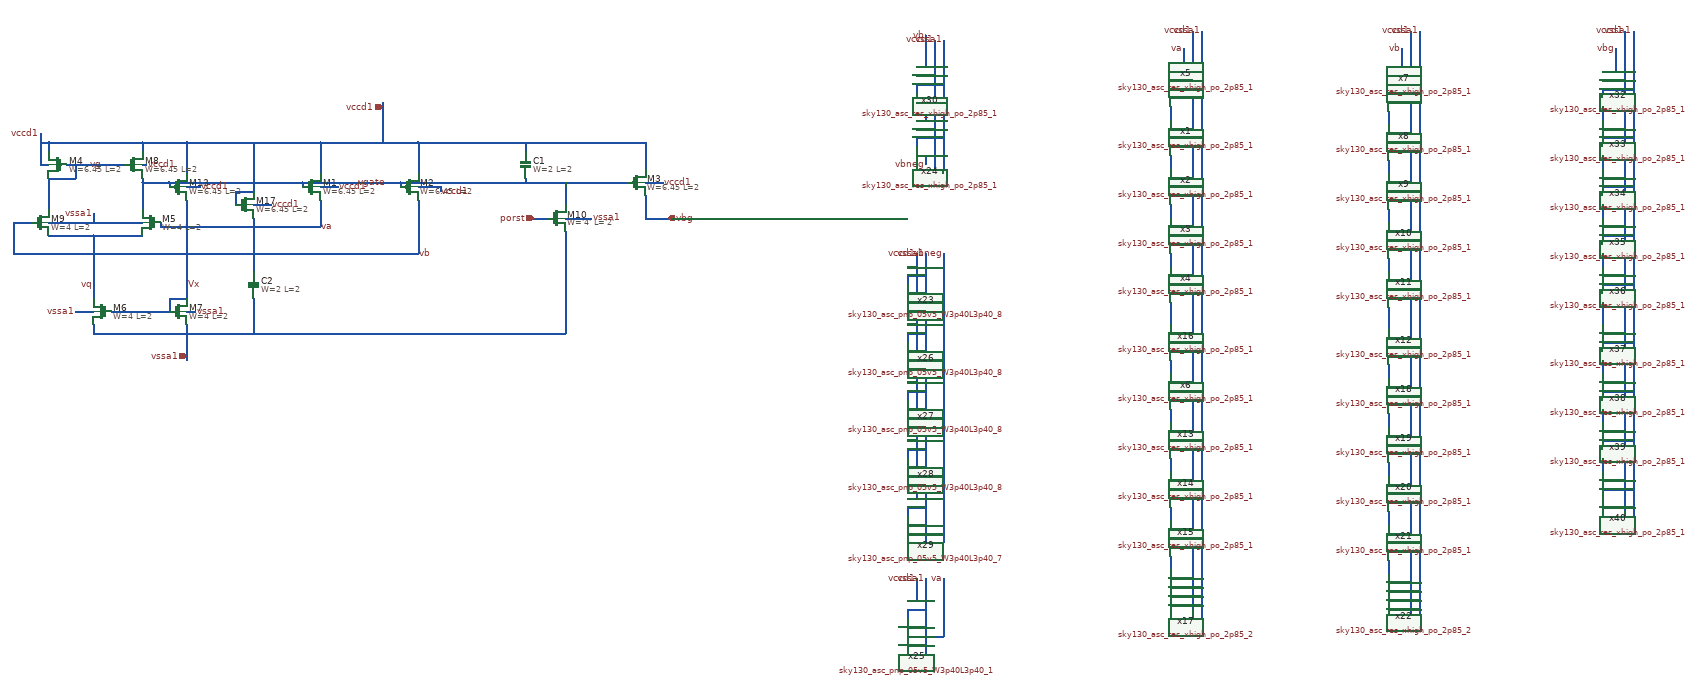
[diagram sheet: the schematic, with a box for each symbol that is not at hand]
v {xschem version=3.0.0 file_version=1.2 }
G {}
K {}
V {}
S {}
E {}
N 2040 520 2260 520 { lab=vccd1}
N 2260 520 2460 520 { lab=vccd1}
N 1430 600 1490 600 { lab=vg}
N 1490 570 1490 600 { lab=vg}
N 1470 570 1490 570 { lab=vg}
N 1490 570 1600 570 { lab=vg}
N 1430 520 1430 540 { lab=vccd1}
N 1430 600 1430 670 { lab=vg}
N 1640 610 1640 670 { lab=vgate}
N 1630 730 1640 730 { lab=vq}
N 1640 570 1650 570 { lab=vccd1}
N 1420 570 1430 570 { lab=vccd1}
N 1430 700 1440 700 { lab=vssa1}
N 1630 700 1640 700 { lab=vssa1}
N 1520 900 1530 900 { lab=vssa1}
N 1570 900 1700 900 { lab=Vx}
N 1740 900 1750 900 { lab=vssa1}
N 1700 870 1700 900 { lab=Vx}
N 1700 870 1740 870 { lab=Vx}
N 2650 520 2770 520 { lab=vccd1}
N 2260 520 2260 590 { lab=vccd1}
N 2770 610 2780 610 { lab=vccd1}
N 2220 610 2220 620 { lab=vgate}
N 2000 610 2000 620 { lab=vgate}
N 1740 620 1750 620 { lab=vccd1}
N 2040 620 2050 620 { lab=vccd1}
N 2040 520 2040 590 { lab=vccd1}
N 2260 620 2270 620 { lab=vccd1}
N 1780 520 2040 520 { lab=vccd1}
N 2700 610 2730 610 { lab=vgate}
N 1700 610 1700 620 { lab=vgate}
N 1740 520 1740 590 { lab=vccd1}
N 1910 710 2040 710 { lab=va}
N 2770 520 2770 580 { lab=vccd1}
N 1430 520 1640 520 { lab=vccd1}
N 1430 730 1440 730 { lab=vq}
N 1530 730 1630 730 { lab=vq}
N 2460 520 2650 520 { lab=vccd1}
N 1740 650 1740 840 { lab=Vx}
N 2000 610 2220 610 { lab=vgate}
N 2220 610 2700 610 { lab=vgate}
N 1440 730 1530 730 { lab=vq}
N 1640 600 1640 610 { lab=vgate}
N 1640 610 1700 610 { lab=vgate}
N 1640 520 1740 520 { lab=vccd1}
N 1440 700 1630 700 { lab=vssa1}
N 1740 520 1780 520 { lab=vccd1}
N 1840 610 2000 610 { lab=vgate}
N 1700 610 1840 610 { lab=vgate}
N 2590 690 2600 690 { lab=vssa1}
N 2590 610 2590 660 { lab=vgate}
N 2500 520 2500 540 { lab=vccd1}
N 2500 600 2500 610 { lab=vgate}
N 1830 710 1910 710 { lab=va}
N 1370 770 2150 770 { lab=#net1}
N 2040 650 2040 710 { lab=va}
N 1680 710 1830 710 { lab=va}
N 1680 700 1680 710 { lab=va}
N 1890 690 1890 710 { lab=va}
N 1850 630 1890 630 { lab=vccd1}
N 1850 630 1850 660 { lab=vccd1}
N 1890 520 1890 630 { lab=vccd1}
N 2770 690 2830 690 { lab=vbg}
N 2150 770 2260 770 { lab=#net1}
N 2180 450 2180 520 { lab=vccd1}
N 2780 610 2810 610 { lab=vccd1}
N 2310 620 2310 630 { lab=vccd1}
N 2270 620 2310 620 { lab=vccd1}
N 2050 620 2080 620 { lab=vccd1}
N 1750 620 1770 620 { lab=vccd1}
N 1640 520 1640 540 { lab=vccd1}
N 1410 570 1420 570 { lab=vccd1}
N 1410 500 1410 570 { lab=vccd1}
N 2600 690 2650 690 { lab=vssa1}
N 1890 660 1930 660 { lab=vccd1}
N 2510 690 2550 690 { lab=porst}
N 1750 900 1760 900 { lab=vssa1}
N 1490 900 1520 900 { lab=vssa1}
N 1530 680 1530 700 { lab=vssa1}
N 1350 700 1390 700 { lab=#net1}
N 1350 700 1350 770 { lab=#net1}
N 1350 770 1370 770 { lab=#net1}
N 2180 430 2180 450 { lab=vccd1}
N 4000 390 4000 1510 { lab=vccd1}
N 4000 310 4000 390 { lab=vccd1}
N 4020 310 4020 1590 { lab=vssa1}
N 4000 270 4000 310 { lab=vccd1}
N 4020 270 4020 310 { lab=vssa1}
N 4470 310 4470 370 { lab=vb}
N 4490 270 4490 310 { lab=vccd1}
N 4510 270 4510 310 { lab=vssa1}
N 4970 310 4970 390 { lab=vccd1}
N 4970 270 4970 310 { lab=vccd1}
N 4990 270 4990 310 { lab=vssa1}
N 4990 310 4990 1310 { lab=vssa1}
N 2770 640 2770 690 { lab=vbg}
N 3400 280 3400 350 { lab=vb}
N 3420 380 3420 500 { lab=vccd1}
N 3440 400 3440 520 { lab=vssa1}
N 3420 290 3420 380 { lab=vccd1}
N 3440 290 3440 400 { lab=vssa1}
N 2260 650 2260 740 { lab=#net1}
N 3380 770 3380 1280 { lab=vccd1}
N 3400 770 3400 1300 { lab=vssa1}
N 3440 770 3440 1340 { lab=vbneg}
N 1740 950 1740 1010 { lab=vssa1}
N 3440 1500 3440 1620 { lab=va}
N 1740 840 1740 870 { lab=Vx}
N 1530 930 1530 950 { lab=vssa1}
N 1530 950 1740 950 { lab=vssa1}
N 1740 930 1740 950 { lab=vssa1}
N 1530 730 1530 870 { lab=vq}
N 2590 720 2590 950 { lab=vssa1}
N 1740 950 2590 950 { lab=vssa1}
N 1890 710 1890 810 { lab=va}
N 1890 870 1890 950 { lab=vssa1}
N 2260 740 2260 770 { lab=#net1}
N 1410 520 1430 520 { lab=vccd1}
N 3380 350 3400 350 { lab=vb}
N 3380 370 3420 370 { lab=vccd1}
N 3380 390 3440 390 { lab=vssa1}
N 3380 430 3400 430 { lab=#net2}
N 3400 430 3400 470 { lab=#net2}
N 3380 470 3400 470 { lab=#net2}
N 3380 490 3420 490 { lab=vccd1}
N 3380 550 3400 550 { lab=vbneg}
N 3400 550 3400 570 { lab=vbneg}
N 3440 520 3440 530 { lab=vssa1}
N 3380 510 3440 510 { lab=vssa1}
N 3420 500 3420 580 { lab=vccd1}
N 3440 530 3440 590 { lab=vssa1}
N 3950 360 3980 360 { lab=va}
N 3980 310 3980 360 { lab=va}
N 3950 380 4000 380 { lab=vccd1}
N 3950 490 4000 490 { lab=vccd1}
N 3950 600 4000 600 { lab=vccd1}
N 3950 710 4000 710 { lab=vccd1}
N 3950 820 4000 820 { lab=vccd1}
N 3950 950 4000 950 { lab=vccd1}
N 3950 1280 4000 1280 { lab=vccd1}
N 3950 1390 4000 1390 { lab=vccd1}
N 4000 1510 4000 1570 { lab=vccd1}
N 3950 1500 4000 1500 { lab=vccd1}
N 3950 420 4020 420 { lab=vssa1}
N 3950 400 4020 400 { lab=vssa1}
N 3950 530 4020 530 { lab=vssa1}
N 3950 640 4020 640 { lab=vssa1}
N 3950 750 4020 750 { lab=vssa1}
N 3950 860 4020 860 { lab=vssa1}
N 3950 990 4020 990 { lab=vssa1}
N 3950 1100 4020 1100 { lab=vssa1}
N 3950 1210 4020 1210 { lab=vssa1}
N 3950 1060 4000 1060 { lab=vccd1}
N 3950 1170 4000 1170 { lab=vccd1}
N 3950 1320 4020 1320 { lab=vssa1}
N 3950 1300 4020 1300 { lab=vssa1}
N 3950 1430 4020 1430 { lab=vssa1}
N 3950 1410 4020 1410 { lab=vssa1}
N 3950 1520 4020 1520 { lab=vssa1}
N 3950 1540 4020 1540 { lab=vssa1}
N 3950 1560 4020 1560 { lab=vssa1}
N 3950 1450 3950 1480 { lab=#net3}
N 3950 1340 3950 1370 { lab=#net4}
N 3950 1190 4020 1190 { lab=vssa1}
N 3950 1230 3950 1260 { lab=#net5}
N 3950 1080 4020 1080 { lab=vssa1}
N 3950 730 4020 730 { lab=vssa1}
N 3950 440 3950 470 { lab=#net6}
N 3950 510 4020 510 { lab=vssa1}
N 3950 550 3950 580 { lab=#net7}
N 3950 620 4020 620 { lab=vssa1}
N 3950 660 3950 690 { lab=#net8}
N 3950 770 3950 800 { lab=#net9}
N 3950 840 4020 840 { lab=vssa1}
N 3950 880 3950 930 { lab=#net10}
N 3950 970 4020 970 { lab=vssa1}
N 3950 1010 3950 1040 { lab=#net11}
N 3950 1120 3950 1150 { lab=#net12}
N 4490 400 4490 1520 { lab=vccd1}
N 4440 370 4470 370 { lab=vb}
N 4440 390 4490 390 { lab=vccd1}
N 4440 500 4490 500 { lab=vccd1}
N 4440 610 4490 610 { lab=vccd1}
N 4440 720 4490 720 { lab=vccd1}
N 4440 830 4490 830 { lab=vccd1}
N 4440 960 4490 960 { lab=vccd1}
N 4440 1290 4490 1290 { lab=vccd1}
N 4440 1400 4490 1400 { lab=vccd1}
N 4490 1520 4490 1580 { lab=vccd1}
N 4440 1510 4490 1510 { lab=vccd1}
N 4440 430 4510 430 { lab=vssa1}
N 4440 410 4510 410 { lab=vssa1}
N 4440 540 4510 540 { lab=vssa1}
N 4440 650 4510 650 { lab=vssa1}
N 4440 760 4510 760 { lab=vssa1}
N 4440 870 4510 870 { lab=vssa1}
N 4440 1000 4510 1000 { lab=vssa1}
N 4440 1110 4510 1110 { lab=vssa1}
N 4440 1220 4510 1220 { lab=vssa1}
N 4440 1070 4490 1070 { lab=vccd1}
N 4440 1180 4490 1180 { lab=vccd1}
N 4440 1330 4510 1330 { lab=vssa1}
N 4440 1310 4510 1310 { lab=vssa1}
N 4440 1440 4510 1440 { lab=vssa1}
N 4440 1420 4510 1420 { lab=vssa1}
N 4440 1530 4510 1530 { lab=vssa1}
N 4440 1550 4510 1550 { lab=vssa1}
N 4440 1570 4510 1570 { lab=vssa1}
N 4440 1460 4440 1490 { lab=#net13}
N 4440 1350 4440 1380 { lab=#net14}
N 4440 1200 4510 1200 { lab=vssa1}
N 4440 1240 4440 1270 { lab=#net15}
N 4440 1090 4510 1090 { lab=vssa1}
N 4440 740 4510 740 { lab=vssa1}
N 4440 450 4440 480 { lab=#net16}
N 4440 520 4510 520 { lab=vssa1}
N 4440 560 4440 590 { lab=#net17}
N 4440 630 4510 630 { lab=vssa1}
N 4440 670 4440 700 { lab=#net18}
N 4440 780 4440 810 { lab=#net19}
N 4440 850 4510 850 { lab=vssa1}
N 4440 890 4440 940 { lab=#net20}
N 4440 980 4510 980 { lab=vssa1}
N 4440 1020 4440 1050 { lab=#net21}
N 4440 1130 4440 1160 { lab=#net22}
N 4490 390 4490 400 { lab=vccd1}
N 4490 310 4490 390 { lab=vccd1}
N 4510 310 4510 1580 { lab=vssa1}
N 4970 390 4970 1350 { lab=vccd1}
N 4990 1310 4990 1360 { lab=vssa1}
N 4920 360 4950 360 { lab=vbg}
N 4950 310 4950 360 { lab=vbg}
N 4920 380 4970 380 { lab=vccd1}
N 4920 490 4970 490 { lab=vccd1}
N 4920 600 4970 600 { lab=vccd1}
N 4920 710 4970 710 { lab=vccd1}
N 4920 820 4970 820 { lab=vccd1}
N 4920 950 4970 950 { lab=vccd1}
N 4920 1060 4970 1060 { lab=vccd1}
N 4920 1170 4970 1170 { lab=vccd1}
N 4920 1280 4970 1280 { lab=vccd1}
N 4920 400 4990 400 { lab=vssa1}
N 4920 400 4920 420 { lab=vssa1}
N 4920 510 4920 530 { lab=vssa1}
N 4920 510 4990 510 { lab=vssa1}
N 4920 620 4920 640 { lab=vssa1}
N 4920 620 4990 620 { lab=vssa1}
N 4920 730 4920 750 { lab=vssa1}
N 4920 730 4990 730 { lab=vssa1}
N 4920 840 4920 860 { lab=vssa1}
N 4920 840 4990 840 { lab=vssa1}
N 4920 970 4920 990 { lab=vssa1}
N 4920 970 4990 970 { lab=vssa1}
N 4920 1080 4920 1100 { lab=vssa1}
N 4920 1080 4990 1080 { lab=vssa1}
N 4920 1190 4920 1210 { lab=vssa1}
N 4920 1190 4990 1190 { lab=vssa1}
N 4920 1300 4920 1320 { lab=vssa1}
N 4920 1300 4990 1300 { lab=vssa1}
N 4920 1120 4920 1150 { lab=#net23}
N 4920 1230 4920 1260 { lab=#net24}
N 4920 1340 4990 1340 { lab=vssa1}
N 4920 440 4920 470 { lab=#net25}
N 4920 550 4920 580 { lab=#net26}
N 4920 660 4920 690 { lab=#net27}
N 4920 770 4920 800 { lab=#net28}
N 4920 880 4920 930 { lab=#net29}
N 4920 1010 4920 1040 { lab=#net30}
N 3380 390 3380 410 { lab=vssa1}
N 3380 510 3380 530 { lab=vssa1}
N 3360 1550 3380 1550 { lab=vccd1}
N 3380 1500 3380 1550 { lab=vccd1}
N 3360 1570 3400 1570 { lab=vssa1}
N 3400 1500 3400 1570 { lab=vssa1}
N 3360 1570 3360 1590 { lab=vssa1}
N 3360 800 3380 800 { lab=vccd1}
N 3360 820 3360 840 { lab=vssa1}
N 3360 820 3400 820 { lab=vssa1}
N 3360 860 3400 860 { lab=vssa1}
N 3360 880 3440 880 { lab=vbneg}
N 3360 1010 3440 1010 { lab=vbneg}
N 3360 1140 3440 1140 { lab=vbneg}
N 3400 1300 3400 1420 { lab=vssa1}
N 3440 1340 3440 1420 { lab=vbneg}
N 3360 1400 3440 1400 { lab=vbneg}
N 3360 1270 3440 1270 { lab=vbneg}
N 3360 930 3380 930 { lab=vccd1}
N 3360 1060 3380 1060 { lab=vccd1}
N 3360 1190 3380 1190 { lab=vccd1}
N 3360 1320 3380 1320 { lab=vccd1}
N 3360 950 3360 970 { lab=vssa1}
N 3360 950 3400 950 { lab=vssa1}
N 3360 1080 3360 1100 { lab=vssa1}
N 3360 1080 3400 1080 { lab=vssa1}
N 3360 990 3400 990 { lab=vssa1}
N 3360 900 3400 900 { lab=vssa1}
N 3360 1030 3400 1030 { lab=vssa1}
N 3360 1120 3400 1120 { lab=vssa1}
N 3360 1160 3400 1160 { lab=vssa1}
N 3360 1210 3360 1230 { lab=vssa1}
N 3360 1210 3400 1210 { lab=vssa1}
N 3360 1250 3400 1250 { lab=vssa1}
N 3360 1290 3400 1290 { lab=vssa1}
N 3360 1340 3360 1360 { lab=vssa1}
N 3360 1340 3400 1340 { lab=vssa1}
N 3360 1380 3400 1380 { lab=vssa1}
N 3360 1420 3400 1420 { lab=vssa1}
N 3380 1280 3380 1320 { lab=vccd1}
N 3360 1630 3440 1630 { lab=va}
N 3440 1620 3440 1630 { lab=va}
N 3400 1570 3400 1670 { lab=vssa1}
N 3360 1610 3400 1610 { lab=vssa1}
N 3360 1650 3400 1650 { lab=vssa1}
C {devices/lab_wire.sym} 2190 610 0 0 {name=l11 lab=vgate}
C {sky130_fd_pr/nfet_01v8_lvt.sym} 1660 700 0 1 {name=M5
L=2
W=4
nf=1
mult=9
ad="'int((nf+1)/2) * W/nf * 0.29'" 
pd="'2*int((nf+1)/2) * (W/nf + 0.29)'"
as="'int((nf+2)/2) * W/nf * 0.29'" 
ps="'2*int((nf+2)/2) * (W/nf + 0.29)'"
nrd="'0.29 / W'" nrs="'0.29 / W'"
sa=0 sb=0 sd=0
model=nfet_01v8_lvt
spiceprefix=X
}
C {sky130_fd_pr/nfet_01v8_lvt.sym} 1550 900 0 1 {name=M6
L=2
W=4
nf=1
mult=1
ad="'int((nf+1)/2) * W/nf * 0.29'" 
pd="'2*int((nf+1)/2) * (W/nf + 0.29)'"
as="'int((nf+2)/2) * W/nf * 0.29'" 
ps="'2*int((nf+2)/2) * (W/nf + 0.29)'"
nrd="'0.29 / W'" nrs="'0.29 / W'"
sa=0 sb=0 sd=0
model=nfet_01v8_lvt
spiceprefix=X
}
C {sky130_fd_pr/nfet_01v8_lvt.sym} 1410 700 0 0 {name=M9
L=2
W=4
nf=1
mult=9
ad="'int((nf+1)/2) * W/nf * 0.29'" 
pd="'2*int((nf+1)/2) * (W/nf + 0.29)'"
as="'int((nf+2)/2) * W/nf * 0.29'" 
ps="'2*int((nf+2)/2) * (W/nf + 0.29)'"
nrd="'0.29 / W'" nrs="'0.29 / W'"
sa=0 sb=0 sd=0
model=nfet_01v8_lvt
spiceprefix=X
}
C {devices/lab_pin.sym} 1550 570 1 0 {name=l2 lab=vg}
C {devices/lab_pin.sym} 1740 840 2 0 {name=l12 lab=Vx}
C {devices/lab_pin.sym} 1530 840 0 0 {name=l18 lab=vq}
C {sky130_fd_pr/nfet_01v8_lvt.sym} 1720 900 0 0 {name=M7
L=2
W=4
nf=1
mult=1
ad="'int((nf+1)/2) * W/nf * 0.29'" 
pd="'2*int((nf+1)/2) * (W/nf + 0.29)'"
as="'int((nf+2)/2) * W/nf * 0.29'" 
ps="'2*int((nf+2)/2) * (W/nf + 0.29)'"
nrd="'0.29 / W'" nrs="'0.29 / W'"
sa=0 sb=0 sd=0
model=nfet_01v8_lvt
spiceprefix=X
}
C {sky130_fd_pr/pfet_01v8_lvt.sym} 1720 620 0 0 {name=M13
L=2
W=6.45
nf=1
mult=12
ad="'int((nf+1)/2) * W/nf * 0.29'" 
pd="'2*int((nf+1)/2) * (W/nf + 0.29)'"
as="'int((nf+2)/2) * W/nf * 0.29'" 
ps="'2*int((nf+2)/2) * (W/nf + 0.29)'"
nrd="'0.29 / W'" nrs="'0.29 / W'"
sa=0 sb=0 sd=0
model=pfet_01v8_lvt
spiceprefix=X
}
C {sky130_fd_pr/pfet_01v8_lvt.sym} 2020 620 0 0 {name=M1
L=2
W=6.45
nf=1
mult=60
ad="'int((nf+1)/2) * W/nf * 0.29'" 
pd="'2*int((nf+1)/2) * (W/nf + 0.29)'"
as="'int((nf+2)/2) * W/nf * 0.29'" 
ps="'2*int((nf+2)/2) * (W/nf + 0.29)'"
nrd="'0.29 / W'" nrs="'0.29 / W'"
sa=0 sb=0 sd=0
model=pfet_01v8_lvt
spiceprefix=X
}
C {sky130_fd_pr/pfet_01v8_lvt.sym} 2240 620 0 0 {name=M2
L=2
W=6.45
nf=1
mult=60
ad="'int((nf+1)/2) * W/nf * 0.29'" 
pd="'2*int((nf+1)/2) * (W/nf + 0.29)'"
as="'int((nf+2)/2) * W/nf * 0.29'" 
ps="'2*int((nf+2)/2) * (W/nf + 0.29)'"
nrd="'0.29 / W'" nrs="'0.29 / W'"
sa=0 sb=0 sd=0
model=pfet_01v8_lvt
spiceprefix=X
}
C {sky130_fd_pr/pfet_01v8_lvt.sym} 2750 610 0 0 {name=M3
L=2
W=6.45
nf=1
mult=60
ad="'int((nf+1)/2) * W/nf * 0.29'" 
pd="'2*int((nf+1)/2) * (W/nf + 0.29)'"
as="'int((nf+2)/2) * W/nf * 0.29'" 
ps="'2*int((nf+2)/2) * (W/nf + 0.29)'"
nrd="'0.29 / W'" nrs="'0.29 / W'"
sa=0 sb=0 sd=0
model=pfet_01v8_lvt
spiceprefix=X
}
C {sky130_fd_pr/pfet_01v8_lvt.sym} 1450 570 0 1 {name=M4
L=2
W=6.45
nf=1
mult=6
ad="'int((nf+1)/2) * W/nf * 0.29'" 
pd="'2*int((nf+1)/2) * (W/nf + 0.29)'"
as="'int((nf+2)/2) * W/nf * 0.29'" 
ps="'2*int((nf+2)/2) * (W/nf + 0.29)'"
nrd="'0.29 / W'" nrs="'0.29 / W'"
sa=0 sb=0 sd=0
model=pfet_01v8_lvt
spiceprefix=X
}
C {sky130_fd_pr/pfet_01v8_lvt.sym} 1620 570 0 0 {name=M8
L=2
W=6.45
nf=1
mult=6
ad="'int((nf+1)/2) * W/nf * 0.29'" 
pd="'2*int((nf+1)/2) * (W/nf + 0.29)'"
as="'int((nf+2)/2) * W/nf * 0.29'" 
ps="'2*int((nf+2)/2) * (W/nf + 0.29)'"
nrd="'0.29 / W'" nrs="'0.29 / W'"
sa=0 sb=0 sd=0
model=pfet_01v8_lvt
spiceprefix=X
}
C {sky130_fd_pr/nfet_01v8_lvt.sym} 2570 690 0 0 {name=M10
L='2'
W='4'
nf=1
mult=9
ad="'int((nf+1)/2) * W/nf * 0.29'" 
pd="'2*int((nf+1)/2) * (W/nf + 0.29)'"
as="'int((nf+2)/2) * W/nf * 0.29'" 
ps="'2*int((nf+2)/2) * (W/nf + 0.29)'"
nrd="'0.29 / W'" nrs="'0.29 / W'"
sa=0 sb=0 sd=0
model=nfet_01v8_lvt
spiceprefix=X
}
C {sky130_fd_pr/pfet_01v8_lvt.sym} 1870 660 0 0 {name=M17
L=2
W=6.45
nf=1
mult=12
ad="'int((nf+1)/2) * W/nf * 0.29'" 
pd="'2*int((nf+1)/2) * (W/nf + 0.29)'"
as="'int((nf+2)/2) * W/nf * 0.29'" 
ps="'2*int((nf+2)/2) * (W/nf + 0.29)'"
nrd="'0.29 / W'" nrs="'0.29 / W'"
sa=0 sb=0 sd=0
model=pfet_01v8_lvt
spiceprefix=X
}
C {devices/ipin.sym} 2520 690 0 0 {name=p1 lab=porst}
C {devices/opin.sym} 2820 690 0 0 {name=p2 lab=vbg}
C {sky130_fd_pr/cap_mim_m3_1.sym} 2500 570 2 0 {name=C1 model=cap_mim_m3_1 W=2 L=2 MF=100 spiceprefix=X}
C {sky130_fd_pr/cap_mim_m3_1.sym} 1890 840 2 0 {name=C2 model=cap_mim_m3_1 W=2 L=2 MF=100 spiceprefix=X}
C {devices/ipin.sym} 2180 440 1 0 {name=p5 lab=vccd1}
C {devices/ipin.sym} 1740 1000 3 0 {name=p6 lab=vssa1}
C {devices/lab_pin.sym} 2810 610 2 0 {name=l1 sig_type=std_logic lab=vccd1}
C {devices/lab_pin.sym} 2310 630 2 0 {name=l3 sig_type=std_logic lab=vccd1}
C {devices/lab_pin.sym} 2080 620 2 0 {name=l5 sig_type=std_logic lab=vccd1}
C {devices/lab_pin.sym} 1770 620 2 0 {name=l6 sig_type=std_logic lab=vccd1}
C {devices/lab_pin.sym} 1650 570 2 0 {name=l7 sig_type=std_logic lab=vccd1}
C {devices/lab_pin.sym} 1410 500 1 0 {name=l8 sig_type=std_logic lab=vccd1}
C {devices/lab_pin.sym} 2650 690 2 0 {name=l9 sig_type=std_logic lab=vssa1}
C {devices/lab_pin.sym} 1930 660 2 0 {name=l13 sig_type=std_logic lab=vccd1}
C {devices/lab_pin.sym} 1760 900 2 0 {name=l16 sig_type=std_logic lab=vssa1}
C {devices/lab_pin.sym} 1490 900 0 0 {name=l17 sig_type=std_logic lab=vssa1}
C {devices/lab_pin.sym} 1530 680 1 0 {name=l19 sig_type=std_logic lab=vssa1}
C {devices/lab_pin.sym} 3980 310 1 0 {name=l20 sig_type=std_logic lab=va
}
C {devices/lab_pin.sym} 4000 270 1 0 {name=l22 sig_type=std_logic lab=vccd1

}
C {devices/lab_pin.sym} 4020 270 1 0 {name=l23 sig_type=std_logic lab=vssa1


}
C {devices/lab_pin.sym} 4470 310 1 0 {name=l21 sig_type=std_logic lab=vb
}
C {devices/lab_pin.sym} 4490 270 1 0 {name=l24 sig_type=std_logic lab=vccd1

}
C {devices/lab_pin.sym} 4510 270 1 0 {name=l25 sig_type=std_logic lab=vssa1


}
C {devices/lab_pin.sym} 4950 310 1 0 {name=l26 sig_type=std_logic lab=vbg

}
C {devices/lab_pin.sym} 4970 270 1 0 {name=l27 sig_type=std_logic lab=vccd1

}
C {devices/lab_pin.sym} 4990 270 1 0 {name=l28 sig_type=std_logic lab=vssa1


}
C {devices/lab_pin.sym} 3400 280 1 0 {name=l10 sig_type=std_logic lab=vb
}
C {devices/lab_pin.sym} 3400 570 0 0 {name=l29 lab=vbneg}
C {devices/lab_pin.sym} 3420 290 1 0 {name=l30 sig_type=std_logic lab=vccd1

}
C {devices/lab_pin.sym} 3440 290 1 0 {name=l31 sig_type=std_logic lab=vssa1


}
C {devices/lab_pin.sym} 3380 770 1 0 {name=l15 sig_type=std_logic lab=vccd1

}
C {devices/lab_pin.sym} 3400 770 1 0 {name=l32 sig_type=std_logic lab=vssa1


}
C {devices/lab_pin.sym} 3440 770 1 0 {name=l34 lab=vbneg}
C {devices/lab_pin.sym} 3440 1500 1 0 {name=l4 sig_type=std_logic lab=va
}
C {devices/lab_pin.sym} 3380 1500 1 0 {name=l14 sig_type=std_logic lab=vccd1

}
C {devices/lab_pin.sym} 3400 1500 1 0 {name=l36 sig_type=std_logic lab=vssa1


}
C {multiple_bgr/sky130_asc_res_xhigh_po_2p85_1.sym} 3230 390 0 0 {name=x30}
C {multiple_bgr/sky130_asc_res_xhigh_po_2p85_1.sym} 3230 510 0 0 {name=x24}
C {multiple_bgr/sky130_asc_res_xhigh_po_2p85_1.sym} 3800 400 0 0 {name=x5}
C {multiple_bgr/sky130_asc_res_xhigh_po_2p85_1.sym} 3800 510 0 0 {name=x1}
C {multiple_bgr/sky130_asc_res_xhigh_po_2p85_1.sym} 3800 620 0 0 {name=x2}
C {multiple_bgr/sky130_asc_res_xhigh_po_2p85_1.sym} 3800 730 0 0 {name=x3}
C {multiple_bgr/sky130_asc_res_xhigh_po_2p85_1.sym} 3800 840 0 0 {name=x4}
C {multiple_bgr/sky130_asc_res_xhigh_po_2p85_1.sym} 3800 970 0 0 {name=x16}
C {multiple_bgr/sky130_asc_res_xhigh_po_2p85_1.sym} 3800 1080 0 0 {name=x6}
C {multiple_bgr/sky130_asc_res_xhigh_po_2p85_1.sym} 3800 1190 0 0 {name=x13}
C {multiple_bgr/sky130_asc_res_xhigh_po_2p85_1.sym} 3800 1300 0 0 {name=x14}
C {multiple_bgr/sky130_asc_res_xhigh_po_2p85_1.sym} 3800 1410 0 0 {name=x15}
C {multiple_bgr/sky130_asc_res_xhigh_po_2p85_2.sym} 3800 1520 0 0 {name=x17}
C {multiple_bgr/sky130_asc_res_xhigh_po_2p85_1.sym} 4290 410 0 0 {name=x7}
C {multiple_bgr/sky130_asc_res_xhigh_po_2p85_1.sym} 4290 520 0 0 {name=x8}
C {multiple_bgr/sky130_asc_res_xhigh_po_2p85_1.sym} 4290 630 0 0 {name=x9}
C {multiple_bgr/sky130_asc_res_xhigh_po_2p85_1.sym} 4290 740 0 0 {name=x10}
C {multiple_bgr/sky130_asc_res_xhigh_po_2p85_1.sym} 4290 850 0 0 {name=x11}
C {multiple_bgr/sky130_asc_res_xhigh_po_2p85_1.sym} 4290 980 0 0 {name=x12}
C {multiple_bgr/sky130_asc_res_xhigh_po_2p85_1.sym} 4290 1090 0 0 {name=x18}
C {multiple_bgr/sky130_asc_res_xhigh_po_2p85_1.sym} 4290 1200 0 0 {name=x19}
C {multiple_bgr/sky130_asc_res_xhigh_po_2p85_1.sym} 4290 1310 0 0 {name=x20}
C {multiple_bgr/sky130_asc_res_xhigh_po_2p85_1.sym} 4290 1420 0 0 {name=x21}
C {multiple_bgr/sky130_asc_res_xhigh_po_2p85_2.sym} 4290 1530 0 0 {name=x22}
C {multiple_bgr/sky130_asc_res_xhigh_po_2p85_1.sym} 4770 400 0 0 {name=x32}
C {multiple_bgr/sky130_asc_res_xhigh_po_2p85_1.sym} 4770 510 0 0 {name=x33}
C {multiple_bgr/sky130_asc_res_xhigh_po_2p85_1.sym} 4770 620 0 0 {name=x34}
C {multiple_bgr/sky130_asc_res_xhigh_po_2p85_1.sym} 4770 730 0 0 {name=x35}
C {multiple_bgr/sky130_asc_res_xhigh_po_2p85_1.sym} 4770 840 0 0 {name=x36}
C {multiple_bgr/sky130_asc_res_xhigh_po_2p85_1.sym} 4770 970 0 0 {name=x37}
C {multiple_bgr/sky130_asc_res_xhigh_po_2p85_1.sym} 4770 1080 0 0 {name=x38}
C {multiple_bgr/sky130_asc_res_xhigh_po_2p85_1.sym} 4770 1190 0 0 {name=x39}
C {multiple_bgr/sky130_asc_res_xhigh_po_2p85_1.sym} 4770 1300 0 0 {name=x40}
C {multiple_bgr/sky130_asc_pnp_05v5_W3p40L3p40_8.sym} 3210 850 0 0 {name=x23}
C {multiple_bgr/sky130_asc_pnp_05v5_W3p40L3p40_8.sym} 3210 980 0 0 {name=x26}
C {multiple_bgr/sky130_asc_pnp_05v5_W3p40L3p40_8.sym} 3210 1110 0 0 {name=x27}
C {multiple_bgr/sky130_asc_pnp_05v5_W3p40L3p40_8.sym} 3210 1240 0 0 {name=x28}
C {multiple_bgr/sky130_asc_pnp_05v5_W3p40L3p40_7.sym} 3210 1370 0 0 {name=x29}
C {multiple_bgr/sky130_asc_pnp_05v5_W3p40L3p40_1.sym} 3210 1600 0 0 {name=x25}
C {devices/lab_pin.sym} 2040 710 2 0 {name=l33 sig_type=std_logic lab=va
}
C {devices/lab_pin.sym} 2260 770 2 0 {name=l35 sig_type=std_logic lab=vb
}
